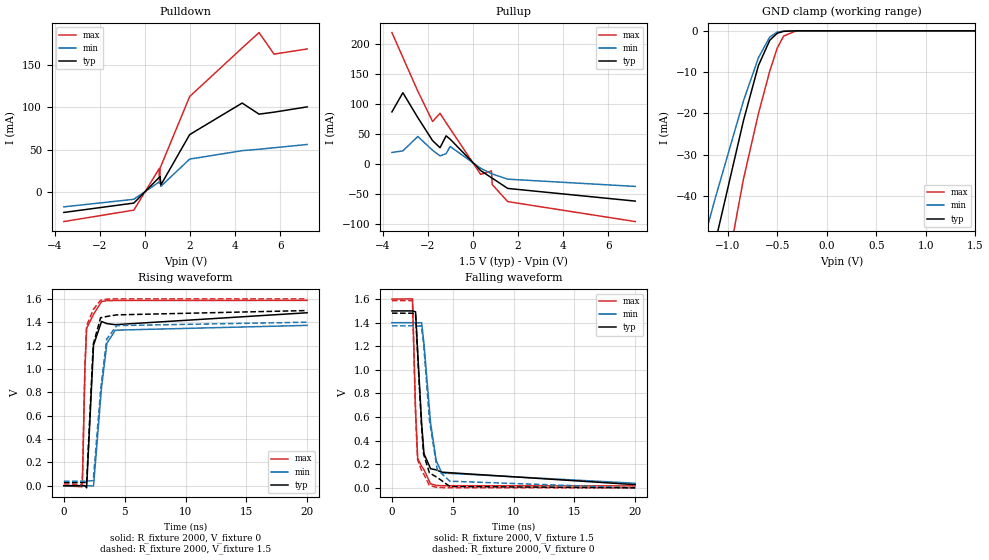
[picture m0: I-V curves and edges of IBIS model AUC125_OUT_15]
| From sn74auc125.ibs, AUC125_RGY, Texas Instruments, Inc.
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[Model]   AUC125_OUT_15
Model_type  3-state
Enable   Active-Low
Vref =   0
Rref =   2000
Cref =   15p
Vmeas =   0.75
| variable   typ   min   max
C_comp   5.28pF   4.71pF   5.53pF
| C_pullup   4.76pF   0.00pF   12.96pF
| C_pulldown   6.36pF   5.33pF   12.83pF
| C_tri-state   5.28pF   4.71pF   5.53pF
[Temperature Range]   40   100   -40
| Ambient temperature   25   85   -40
[Voltage range]   1.5   1.4   1.6
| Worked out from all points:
|   slope of the pulldown table from 0 to 0.225 V, typ, clamps not added: 36.9 ohm
|   slope of the pullup table from 0 to 0.225 V, typ, clamps not added: 29.6 ohm
|   GND clamp passes 1 mA (typ) near -0.53 V on its own axis
|   rising waveform, R_fixture 2000, V_fixture 0: 20-80 % time 405ps typ, 652ps min, 245ps max; typ from 0 V to 1.48 V
|   falling waveform, R_fixture 2000, V_fixture 1.5: 20-80 % time 506ps typ, 801ps min, 274ps max; typ from 1.5 V to 0.027 V
|   rising waveform, R_fixture 2000, V_fixture 1.5: 20-80 % time 399ps typ, 643ps min, 242ps max; typ from 0.027 V to 1.5 V
|   falling waveform, R_fixture 2000, V_fixture 0: 20-80 % time 502ps typ, 789ps min, 272ps max; typ from 1.48 V to 0 V
[GND Clamp]
| AUC125_OUT_15
|   Voltage   I(typ)   I(min)   I(max)
-3.6V     -324.8mA   -272.6mA   -395.3mA
-1.51V    -93.07mA   -74.9mA    -123.7mA
-1.465V   -88.13mA   -70.8mA    -117.8mA
-1.33V    -73.37mA   -58.63mA   -100mA
-1.125V   -51.23mA   -40.54mA   -72.92mA
-840mV    -21.74mA   -16.94mA   -35.88mA
-690mV    -8.435mA   -6.553mA   -20.12mA
-575mV    -2.291mA   -1.489mA   -9.733mA
-500mV    -581.2uA   -306.5uA   -4.204mA
-435mV    -119.5uA   -65.92uA   -1.256mA
-310mV    -3.098uA   -2.805uA   -25.01uA
1.5V      384.9pA    7.753nA    386pA
[Pulldown]
| AUC125_OUT_15
|   Voltage   I(typ)   I(min)   I(max)
-3.6V     -23.87mA   -17.26mA   -34.61mA
-495mV    -12.82mA   -8.371mA   -21.12mA
630mV     17.4mA     12.02mA    27.68mA
640mV     17.65mA    12.19mA    10.5mA
655mV     18.03mA    12.44mA    10.77mA
675mV     18.52mA    12.77mA    29.29mA
705mV     8.519mA    6.901mA    30.51mA
1.985V    67.92mA    39.05mA    112.8mA
4.315V    105.1mA    48.97mA    170.1mA
5.065V    92.04mA    50.67mA    188.2mA
5.73V     94.37mA    52.39mA    162.8mA
7.2V      100.6mA    56.28mA    168.9mA
[Pullup]
| AUC125_OUT_15
|   Voltage   I(typ)   I(min)   I(max)
-3.6V     86.6mA     19.27mA    218.2mA
-3.115V   118.4mA    22.02mA    177.1mA
-2.45V    77.1mA     45.8mA     120.9mA
-1.795V   38.94mA    22.91mA    70.71mA
-1.465V   27.19mA    13.61mA    84.28mA
-1.195V   46.88mA    17.39mA    68.58mA
-1.015V   41.37mA    29.25mA    58.51mA
340mV     -10.71mA   -6.913mA   -17.08mA
820mV     -22.63mA   -15.87mA   -11.24mA
850mV     -23.26mA   -16.33mA   -33.77mA
1.54V     -40.34mA   -24.97mA   -62.2mA
7.2V      -61.35mA   -37.01mA   -95.3mA
[Ramp]
| AUC125_OUT_15
| variable   typ   min   max
dV/dt_r   0.90/4.07E-10   0.84/6.60E-10   0.96/2.48E-10
dV/dt_f   0.89/5.09E-10   0.82/8.06E-10   0.95/2.75E-10
R_load = 2000
[Rising Waveform]
| AUC125_OUT_15
R_fixture =   2000
C_fixture =   0
L_fixture =   0
V_fixture =   0
V_fixture_min = 0
V_fixture_max = 0
|   Time   V(typ)   V(min)   V(max)
0s        7.607nV    28.63nV    898.1pV
1.49ns    1.514uV    -5.607uV   -8.9mV
1.54ns    39.05uV    -7.485uV   92.87mV
1.73ns    319.8uV    -13.31uV   995.4mV
1.87ns    -18.27mV   79.94uV    1.348V
2.44ns    1.204V     -1.752mV   1.468V
3.095ns   1.406V     840.2mV    1.576V
3.54ns    1.388V     1.22V      1.585V
4.23ns    1.379V     1.332V     1.586V
20ns      1.481V     1.373V     1.587V
[Falling Waveform]
| AUC125_OUT_15
R_fixture =   2000
C_fixture =   0
L_fixture =   0
V_fixture =   1.5
V_fixture_min = 1.4
V_fixture_max = 1.6
|   Time   V(typ)   V(min)   V(max)
0s        1.5V       1.4V       1.6V
1.69ns    1.5V       1.4V       1.602V
1.945ns   1.492V     1.4V       646.9mV
2.12ns    1.145V     1.399V     246.9mV
2.44ns    547.4mV    1.4V       182.7mV
2.635ns   289.5mV    1.222V     154mV
3.175ns   162.5mV    551.8mV    33.89mV
3.64ns    152.3mV    230.8mV    20.8mV
4.1ns     132.8mV    126.3mV    18.08mV
20ns      27.21mV    38.79mV    16.42mV
[Rising Waveform]
| AUC125_OUT_15
R_fixture =   2000
C_fixture =   0
L_fixture =   0
V_fixture =   1.5
V_fixture_min = 1.4
V_fixture_max = 1.6
|   Time   V(typ)   V(min)   V(max)
0s        27.17mV    38.77mV    16.4mV
1.49ns    27.17mV    38.76mV    8.867mV
1.54ns    27.21mV    38.76mV    117.9mV
1.73ns    27.54mV    38.76mV    1.025V
1.87ns    17.88mV    38.85mV    1.37V
2.415ns   1.211V     44.01mV    1.508V
3.02ns    1.438V     817.1mV    1.588V
3.515ns   1.449V     1.254V     1.598V
4.345ns   1.463V     1.371V     1.6V
20ns      1.5V       1.4V       1.6V
[Falling Waveform]
| AUC125_OUT_15
R_fixture =   2000
C_fixture =   0
L_fixture =   0
V_fixture =   0
V_fixture_min = 0
V_fixture_max = 0
|   Time   V(typ)   V(min)   V(max)
0s        1.481V     1.373V     1.587V
1.69ns    1.48V      1.373V     1.588V
1.94ns    1.473V     1.372V     644mV
2.11ns    1.139V     1.371V     238.6mV
2.42ns    544.6mV    1.373V     151.8mV
2.605ns   285.3mV    1.22V      117.6mV
3.085ns   126.1mV    573.5mV    19.59mV
3.72ns    88.77mV    155.4mV    3.251mV
4.765ns   11.37mV    56.31mV    469.4uV
20ns      37.3uV     14.59uV    14.72uV
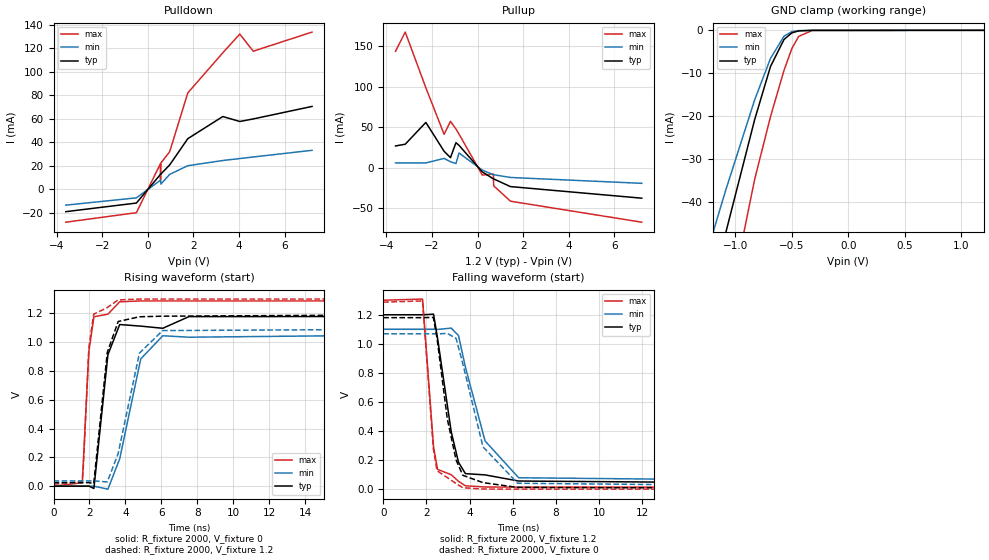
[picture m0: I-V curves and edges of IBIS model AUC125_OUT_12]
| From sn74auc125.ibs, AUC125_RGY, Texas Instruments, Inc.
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[Model]   AUC125_OUT_12
Model_type  3-state
Enable   Active-Low
Vref =   0
Rref =   2000
Cref =   15p
Vmeas =   0.6
| variable   typ   min   max
C_comp   5.39pF   4.85pF   5.66pF
| C_pullup   4.47pF   0.81pF   9.58pF
| C_pulldown   6.19pF   5.48pF   8.82pF
| C_tri-state   5.39pF   4.85pF   5.66pF
[Temperature Range]   40   100   -40
| Ambient temperature   25   85   -40
[Voltage range]   1.2   1.1   1.3
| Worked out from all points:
|   slope of the pulldown table from 0 to 0.18 V, typ, clamps not added: 42.4 ohm
|   slope of the pullup table from 0 to 0.18 V, typ, clamps not added: 38.7 ohm
|   GND clamp passes 1 mA (typ) near -0.53 V on its own axis
|   rising waveform, R_fixture 2000, V_fixture 0: 20-80 % time 587ps typ, 1.06ns min, 319ps max; typ from 0 V to 1.18 V
|   falling waveform, R_fixture 2000, V_fixture 1.2: 20-80 % time 783ps typ, 1.26ns min, 389ps max; typ from 1.2 V to 0.024 V
|   rising waveform, R_fixture 2000, V_fixture 1.2: 20-80 % time 580ps typ, 1.05ns min, 314ps max; typ from 0.024 V to 1.2 V
|   falling waveform, R_fixture 2000, V_fixture 0: 20-80 % time 764ps typ, 1.2ns min, 383ps max; typ from 1.18 V to 0 V
[GND Clamp]
| AUC125_OUT_12
|   Voltage   I(typ)   I(min)   I(max)
-3.6V     -324.8mA   -272.6mA   -395.3mA
-1.455V   -87.03mA   -69.89mA   -116.5mA
-1.285V   -68.47mA   -54.61mA   -94.06mA
-1.12V    -50.69mA   -40.11mA   -72.26mA
-1.085V   -46.97mA   -37.09mA   -67.64mA
-830mV    -20.77mA   -16.17mA   -34.67mA
-690mV    -8.435mA   -6.553mA   -20.12mA
-570mV    -2.125mA   -1.36mA    -9.318mA
-500mV    -581.2uA   -306.5uA   -4.204mA
-440mV    -136.4uA   -74.2uA    -1.408mA
-320mV    -4.212uA   -3.691uA   -36.5uA
1.2V      309.4pA    7.669nA    277.4pA
[Pulldown]
| AUC125_OUT_12
|   Voltage   I(typ)   I(min)   I(max)
-3.6V     -19.18mA   -13.63mA   -28.17mA
-505mV    -11.84mA   -7.409mA   -20.06mA
545mV     12.46mA    7.541mA    21.58mA
550mV     12.55mA    7.59mA     7.985mA
560mV     12.73mA    7.686mA    8.172mA
570mV     12.91mA    4.373mA    22.34mA
955mV     20.69mA    12.6mA     31.94mA
1.75V     43.08mA    20.02mA    82.12mA
3.285V    61.96mA    24.44mA    116.3mA
4.03V     57.75mA    26.13mA    132.3mA
4.62V     59.91mA    27.45mA    117.7mA
7.2V      70.58mA    33.15mA    134mA
[Pullup]
| AUC125_OUT_12
|   Voltage   I(typ)   I(min)   I(max)
-3.6V     26.88mA    5.995mA    143.6mA
-3.175V   28.99mA    5.887mA    167.3mA
-2.27V    55.88mA    5.951mA    98.68mA
-1.47V    20.32mA    11.49mA    41.27mA
-1.19V    12.43mA    7.405mA    57.16mA
-950mV    30.92mA    5.183mA    47.81mA
-815mV    27.63mA    18.17mA    41.5mA
205mV     -5.131mA   -2.956mA   -9.022mA
690mV     -13.63mA   -8.496mA   -7.804mA
705mV     -13.8mA    -8.599mA   -22.27mA
1.44V     -23.26mA   -12.02mA   -41.28mA
7.2V      -37.56mA   -19.23mA   -67.17mA
[Ramp]
| AUC125_OUT_12
| variable   typ   min   max
dV/dt_r   0.72/5.94E-10   0.65/1.08E-09   0.77/3.23E-10
dV/dt_f   0.71/7.85E-10   0.64/1.26E-09   0.78/3.91E-10
R_load = 2000
[Rising Waveform]
| AUC125_OUT_12
R_fixture =   2000
C_fixture =   0
L_fixture =   0
V_fixture =   0
V_fixture_min = 0
V_fixture_max = 0
|   Time   V(typ)   V(min)   V(max)
0s        7.12nV     30.4nV     723.3pV
1.6ns     -6.189uV   -2.033uV   23.85mV
1.965ns   883.1uV    -12.76uV   935.5mV
2.245ns   -16.12mV   -20.3uV    1.177V
3.025ns   913.9mV    -20.74mV   1.195V
3.68ns    1.123V     190.1mV    1.281V
4.85ns    1.112V     884.3mV    1.287V
6.075ns   1.097V     1.045V     1.287V
7.53ns    1.178V     1.035V     1.287V
34.99ns   1.18V      1.069V     1.287V
[Falling Waveform]
| AUC125_OUT_12
R_fixture =   2000
C_fixture =   0
L_fixture =   0
V_fixture =   1.2
V_fixture_min = 1.1
V_fixture_max = 1.3
|   Time   V(typ)   V(min)   V(max)
0s        1.2V       1.1V       1.3V
1.82ns    1.2V       1.1V       1.308V
2.33ns    1.204V     1.1V       290.8mV
2.515ns   1.039V     1.099V     136.3mV
3.15ns    393.5mV    1.108V     99.25mV
3.485ns   185.3mV    1.057V     54mV
3.805ns   106.9mV    839.9mV    23.23mV
4.715ns   98.24mV    331.7mV    14.98mV
6.27ns    55.98mV    78.57mV    14.02mV
34.99ns   24mV       36.64mV    13.87mV
[Rising Waveform]
| AUC125_OUT_12
R_fixture =   2000
C_fixture =   0
L_fixture =   0
V_fixture =   1.2
V_fixture_min = 1.1
V_fixture_max = 1.3
|   Time   V(typ)   V(min)   V(max)
0s        23.98mV    36.63mV    13.86mV
1.58ns    23.97mV    36.63mV    31.94mV
1.645ns   23.97mV    36.62mV    103.3mV
1.965ns   24.79mV    36.62mV    964.5mV
2.235ns   17.93mV    36.61mV    1.195V
2.99ns    929.7mV    29.55mV    1.241V
3.595ns   1.144V     227.5mV    1.294V
4.775ns   1.177V     923.9mV    1.3V
6.065ns   1.181V     1.081V     1.3V
34.99ns   1.2V       1.1V       1.3V
[Falling Waveform]
| AUC125_OUT_12
R_fixture =   2000
C_fixture =   0
L_fixture =   0
V_fixture =   0
V_fixture_min = 0
V_fixture_max = 0
|   Time   V(typ)   V(min)   V(max)
0s        1.18V      1.069V     1.287V
1.82ns    1.18V      1.069V     1.295V
2.32ns    1.182V     1.069V     278.4mV
2.49ns    1.041V     1.068V     127.3mV
2.965ns   485.1mV    1.072V     79.54mV
3.375ns   200.1mV    1.037V     38.33mV
3.685ns   95.38mV    863.1mV    9.826mV
4.62ns    44.95mV    290.8mV    1.066mV
6.225ns   11.99mV    40.69mV    149.6uV
34.99ns   21.93uV    1.329uV    8.405uV
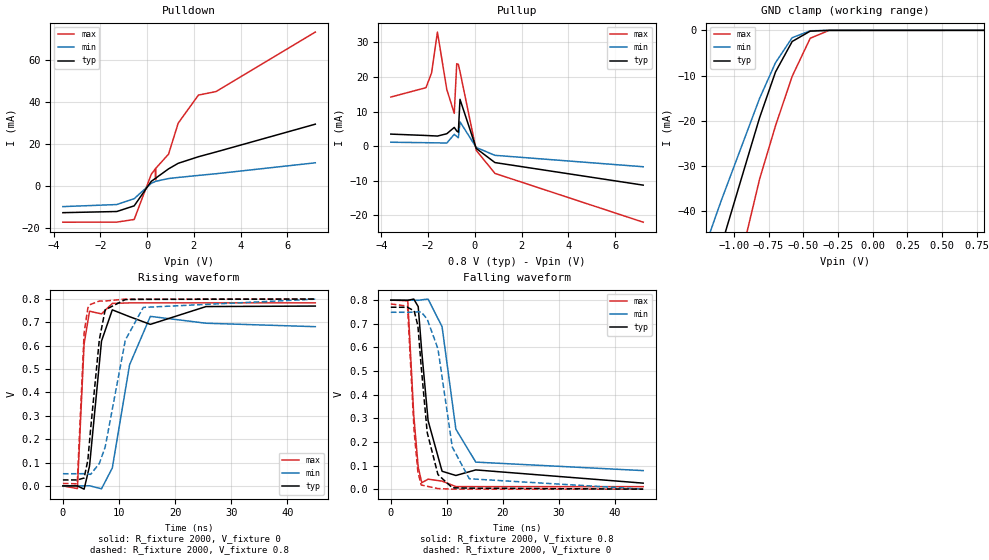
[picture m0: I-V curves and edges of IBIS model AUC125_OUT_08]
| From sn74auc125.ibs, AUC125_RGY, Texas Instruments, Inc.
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[Model]   AUC125_OUT_08
Model_type  3-state
Enable   Active-Low
Vref =   0
Rref =   2000
Cref =   15p
Vmeas =   0.4
| variable   typ   min   max
C_comp   5.50pF   5.00pF   5.70pF
| C_pullup   5.67pF   1.19pF   7.96pF
| C_pulldown   6.37pF   5.71pF   6.83pF
| C_tri-state   5.50pF   5.00pF   5.70pF
[Temperature Range]   40   100   -40
| Ambient temperature   25   85   -40
[Voltage range]   0.8   0.8   0.8
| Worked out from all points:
|   slope of the pulldown table from 0 to 0.12 V, typ, clamps not added: 77.5 ohm
|   slope of the pullup table from 0 to 0.12 V, typ, clamps not added: 93.5 ohm
|   GND clamp passes 1 mA (typ) near -0.53 V on its own axis
|   rising waveform, R_fixture 2000, V_fixture 0: 20-80 % time 1.86ns typ, 2.92ns min, 916ps max; typ from 0 V to 0.77 V
|   falling waveform, R_fixture 2000, V_fixture 0.8: 20-80 % time 2.43ns typ, 2.66ns min, 1.26ns max; typ from 0.8 V to 0.026 V
|   rising waveform, R_fixture 2000, V_fixture 0.8: 20-80 % time 1.86ns typ, 3.48ns min, 875ps max; typ from 0.025 V to 0.8 V
|   falling waveform, R_fixture 2000, V_fixture 0: 20-80 % time 2.06ns typ, 2.93ns min, 1.17ns max; typ from 0.77 V to 0 V
[GND Clamp]
| AUC125_OUT_08
|   Voltage   I(typ)   I(min)   I(max)
-3.6V     -324.8mA   -272.6mA   -395.3mA
-1.465V   -88.13mA   -70.8mA    -117.8mA
-1.33V    -73.37mA   -58.63mA   -100mA
-1.285V   -68.47mA   -54.61mA   -94.06mA
-1.125V   -51.23mA   -40.54mA   -72.92mA
-1.09V    -47.5mA    -37.52mA   -68.3mA
-815mV    -19.32mA   -15.04mA   -32.89mA
-700mV    -9.187mA   -7.147mA   -21.07mA
-580mV    -2.465mA   -1.627mA   -10.15mA
-450mV    -176.7uA   -94.05uA   -1.748mA
-315mV    -3.612uA   -3.219uA   -30.25uA
800mV     222.9pA    406.9pA    175.5pA
[Pulldown]
| AUC125_OUT_08
|   Voltage   I(typ)   I(min)   I(max)
-3.6V     -12.84mA   -9.953mA   -17.38mA
-1.295V   -12.29mA   -8.968mA   -17.35mA
-550mV    -9.589mA   -6.157mA   -16.09mA
180mV     2.098mA    1.151mA    5.42mA
360mV     3.518mA    2.063mA    8.134mA
365mV     3.559mA    2.087mA    2.788mA
370mV     3.599mA    2.112mA    8.262mA
920mV     8.04mA     3.431mA    15.04mA
1.335V    10.7mA     3.951mA    29.86mA
2.2V      13.83mA    4.922mA    43.22mA
2.95V     16.09mA    5.717mA    44.89mA
7.2V      29.35mA    10.93mA    73.25mA
[Pullup]
| AUC125_OUT_08
|   Voltage   I(typ)   I(min)   I(max)
-3.6V     3.469mA    1.12mA     14.19mA
-2.095V   3.073mA    986.3uA    16.9mA
-1.855V   2.995mA    962.2uA    21.18mA
-1.605V   2.907mA    935.6uA    32.98mA
-1.205V   3.573mA    886.9uA    16.4mA
-885mV    5.409mA    3.396mA    9.469mA
-780mV    4.37mA     2.798mA    23.84mA
-710mV    4.028mA    2.41mA     23.63mA
-640mV    13.53mA    7.032mA    21.56mA
55mV      -672.7uA   -397.4uA   -1.232mA
855mV     -4.764mA   -2.667mA   -7.894mA
7.2V      -11.29mA   -5.969mA   -22.01mA
[Ramp]
| AUC125_OUT_08
| variable   typ   min   max
dV/dt_r   0.47/1.88E-09   0.46/3.52E-09   0.48/9.29E-10
dV/dt_f   0.47/2.42E-09   0.44/2.66E-09   0.48/1.27E-09
R_load = 2000
[Rising Waveform]
| AUC125_OUT_08
R_fixture =   2000
C_fixture =   0
L_fixture =   0
V_fixture =   0
V_fixture_min = 0
V_fixture_max = 0
|   Time   V(typ)   V(min)   V(max)
0s        8.744nV    49.66nV    543.3pV
2.585ns   3.001uV    -34.2uV    -11.51mV
3.78ns    -13.99mV   208.5uV    607.6mV
4.75ns    85.33mV    581uV      747.9mV
6.885ns   620.3mV    -12.44mV   736.5mV
8.81ns    753.8mV    76.93mV    781.4mV
11.89ns   724.6mV    518.5mV    783.6mV
15.59ns   691.6mV    725.9mV    783.7mV
25.52ns   767.9mV    696.5mV    783.7mV
45ns      770mV      681.8mV    783.8mV
[Falling Waveform]
| AUC125_OUT_08
R_fixture =   2000
C_fixture =   0
L_fixture =   0
V_fixture =   0.8
V_fixture_min = 0.8
V_fixture_max = 0.8
|   Time   V(typ)   V(min)   V(max)
0s        800mV      800mV      800mV
3.025ns   799.2mV    800mV      797.3mV
4.09ns    804.5mV    799.3mV    313.2mV
4.885ns   772.6mV    799.3mV    93.22mV
5.515ns   582.9mV    801.4mV    27.34mV
6.65ns    289.6mV    804.3mV    42.24mV
9.14ns    75.75mV    687.3mV    34.04mV
11.6ns    57.95mV    253.6mV    10.84mV
15.15ns   81.49mV    114.5mV    10.65mV
45ns      25.52mV    78.56mV    10.61mV
[Rising Waveform]
| AUC125_OUT_08
R_fixture =   2000
C_fixture =   0
L_fixture =   0
V_fixture =   0.8
V_fixture_min = 0.8
V_fixture_max = 0.8
|   Time   V(typ)   V(min)   V(max)
0s        25.46mV    52.12mV    10.6mV
2.555ns   25.49mV    52.13mV    8.979mV
3.785ns   33.78mV    52.33mV    655.4mV
4.455ns   110.8mV    51.06mV    762.5mV
4.935ns   241.7mV    49.1mV     777.2mV
6.495ns   626.1mV    96.24mV    791.5mV
7.54ns    754mV      166.3mV    791.5mV
11.13ns   797.9mV    624.4mV    799.9mV
14.33ns   798.7mV    764.3mV    799.9mV
45ns      800mV      799.6mV    800mV
[Falling Waveform]
| AUC125_OUT_08
R_fixture =   2000
C_fixture =   0
L_fixture =   0
V_fixture =   0
V_fixture_min = 0
V_fixture_max = 0
|   Time   V(typ)   V(min)   V(max)
0s        770mV      748.6mV    783.8mV
2.98ns    769.6mV    748.5mV    774.5mV
4.16ns    754.5mV    748.8mV    242.9mV
4.83ns    691.4mV    750.3mV    72.22mV
5.415ns   519.4mV    749.8mV    17.68mV
6.49ns    239.4mV    719.6mV    12.22mV
8.405ns   61.8mV     594mV      2.516mV
10.96ns   5.932mV    178.1mV    107.1uV
13.99ns   4.303mV    44.05mV    50.02uV
45ns      36.43uV    254.1uV    9.628uV
